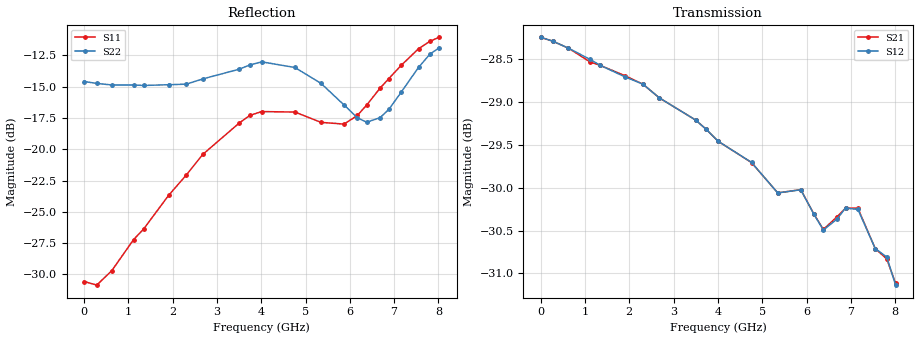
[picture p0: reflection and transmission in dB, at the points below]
! DEVICE ID: PE43712
! File Path: z:\PE43713\PE43713_CHAR_NOM_04292014\AMB\3p300\LS_ATT_27p00dB\PE43713_AMB_3p300V_3p000V_0p000V_LS_ATT_27p00dB_S2P_SN_10_A0139A.s2p
! Serial: 10
! Lot: A0139A
! Temp: 25C
! VDD: 3.300
! VSS: 0.000
! Control_Hi: 3.000
! Control_Lo: 0.000
! Attenuation Step: 27.00dB
! Port 1: RF1
! Port 2: RF2
! ThroughPath:1-2
! IDD: 0.0001454107
! ISS: -1.345e-007
#  Hz  S  RI  R  50
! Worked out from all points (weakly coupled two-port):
!   801 points, 10 MHz to 8.01 GHz, reference 50 ohm
!   highest |S21| = -28.25 dB at 10 MHz (marker M1); lowest = -31.1 dB at 8.01 GHz (marker M2)
!   lowest |S11| = -30.9 dB at 290 MHz (marker M3), VSWR 1.06, Z = 47.4 + j1.03 ohm
!   |S11| at or under -10 dB: start of sweep to end of sweep
!   |S22| runs from -17.9 to -11.9 dB; largest |S21 - S12| = 0.00015
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1e7  -0.0296 0.000779  0.0387 -0.000176  0.0387 -0.000156  -0.1865 0.00122
2.9e8  -0.0265 0.0109  0.0383 -0.00382  0.0383 -0.00383  -0.1823 0.0189
6.3e8  -0.0236 0.0227  0.0373 -0.00796  0.0373 -0.00797  -0.1764 0.039
1.12e9  -0.0179 0.0397  0.035 -0.0133  0.0351 -0.0134  -0.1676 0.0674
1.35e9  -0.0133 0.0462  0.0338 -0.0157  0.0338 -0.0157  -0.1616 0.0789
1.91e9  0.000783 0.0654  0.0303 -0.0208  0.0303 -0.0207  -0.1427 0.1115
2.31e9  0.0137 0.0777  0.0272 -0.0241  0.0272 -0.0241  -0.1267 0.1307
2.68e9  0.0267 0.0915  0.024 -0.0264  0.024 -0.0264  -0.1106 0.1557
3.5e9  0.0457 0.1186  0.0164 -0.0305  0.0164 -0.0305  -0.0863 0.1901
3.74e9  0.0496 0.1271  0.014 -0.0312  0.014 -0.0312  -0.0836 0.2003
4.01e9  0.0534 0.131  0.0113 -0.0317  0.0113 -0.0317  -0.0823 0.2078
4.76e9  0.0637 0.1256  0.00447 -0.0324  0.00452 -0.0324  -0.0668 0.2014
5.35e9  0.0803 0.0998  -0.000267 -0.0314  -0.000277 -0.0314  -0.0503 0.1763
5.87e9  0.1047 0.0702  -0.00462 -0.0312  -0.00458 -0.0312  -0.0127 0.1497
6.17e9  0.1241 0.0568  -0.0078 -0.0295  -0.00776 -0.0295  0.0171 0.1325
6.38e9  0.1411 0.0514  -0.00837 -0.0287  -0.00829 -0.0287  0.0416 0.1213
6.68e9  0.1698 0.0436  -0.0103 -0.0286  -0.0103 -0.0285  0.0788 0.108
6.88e9  0.1873 0.0403  -0.0123 -0.0282  -0.0123 -0.0282  0.1001 0.1039
7.16e9  0.2129 0.0398  -0.0151 -0.0268  -0.015 -0.0268  0.1328 0.1049
7.55e9  0.2484 0.0434  -0.0175 -0.0233  -0.0175 -0.0233  0.1797 0.1133
7.81e9  0.2659 0.0482  -0.0186 -0.0219  -0.0186 -0.022  0.2071 0.1219
8.01e9  0.275 0.0522  -0.0189 -0.0204  -0.0188 -0.0204  0.2207 0.1252
